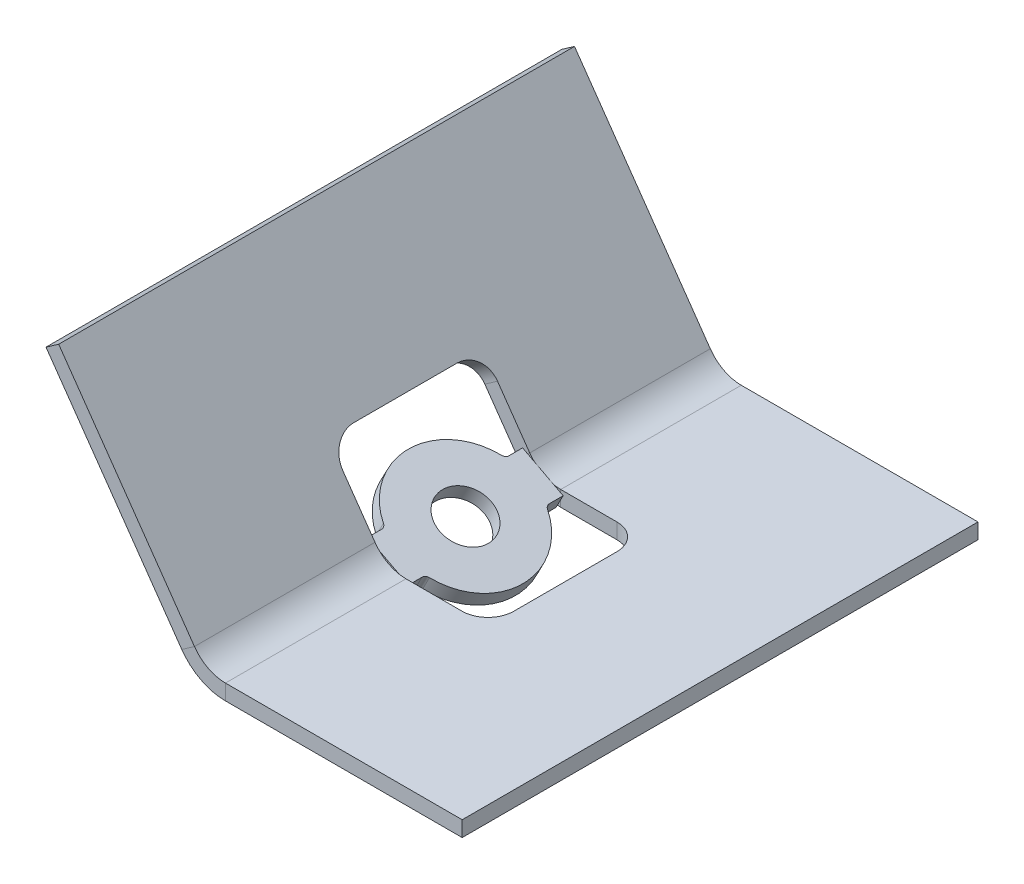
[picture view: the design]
ISO-10303-21;
HEADER;
FILE_DESCRIPTION(('STEP AP214'),'2;1');
FILE_NAME('part.step','',(''),(''),'','','');
FILE_SCHEMA(('AUTOMOTIVE_DESIGN { 1 0 10303 214 1 1 1 1 }'));
ENDSEC;
DATA;
#1=APPLICATION_CONTEXT('core data for automotive mechanical design processes');
#2=APPLICATION_PROTOCOL_DEFINITION('international standard','automotive_design',2000,#1);
#3=PRODUCT_CONTEXT('',#1,'mechanical');
#4=PRODUCT('Part','Part','',(#3));
#5=PRODUCT_RELATED_PRODUCT_CATEGORY('part','',(#4));
#6=PRODUCT_DEFINITION_FORMATION('','',#4);
#7=PRODUCT_DEFINITION_CONTEXT('part definition',#1,'design');
#8=PRODUCT_DEFINITION('design','',#6,#7);
#9=PRODUCT_DEFINITION_SHAPE('','',#8);
#10=(LENGTH_UNIT() NAMED_UNIT(*) SI_UNIT(.MILLI.,.METRE.));
#11=(NAMED_UNIT(*) PLANE_ANGLE_UNIT() SI_UNIT($,.RADIAN.));
#12=(NAMED_UNIT(*) SI_UNIT($,.STERADIAN.) SOLID_ANGLE_UNIT());
#13=UNCERTAINTY_MEASURE_WITH_UNIT(LENGTH_MEASURE(1.E-05),#10,'distance_accuracy_value','');
#14=(GEOMETRIC_REPRESENTATION_CONTEXT(3) GLOBAL_UNCERTAINTY_ASSIGNED_CONTEXT((#13)) GLOBAL_UNIT_ASSIGNED_CONTEXT((#10,
#11,#12)) REPRESENTATION_CONTEXT('',''));
#15=CARTESIAN_POINT('',(0.,0.,0.));
#16=DIRECTION('',(0.,0.,1.));
#17=DIRECTION('',(1.,0.,0.));
#18=AXIS2_PLACEMENT_3D('',#15,#16,#17);
#19=CARTESIAN_POINT('',(-0.740629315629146,-1.42273567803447,0.));
#20=DIRECTION('',(-0.461748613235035,-0.887010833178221,0.));
#21=DIRECTION('',(0.887010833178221,-0.461748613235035,0.));
#22=AXIS2_PLACEMENT_3D('',#19,#20,#21);
#23=PLANE('',#22);
#24=DIRECTION('',(-0.887010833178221,0.461748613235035,0.));
#25=VECTOR('',#24,1.);
#26=CARTESIAN_POINT('',(3.19331177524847,-3.47061578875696,15.));
#27=LINE('',#26,#25);
#28=CARTESIAN_POINT('',(3.19331177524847,-3.47061578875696,15.));
#29=VERTEX_POINT('',#28);
#30=CARTESIAN_POINT('',(-4.67457040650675,0.625144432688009,15.));
#31=VERTEX_POINT('',#30);
#32=EDGE_CURVE('E151',#29,#31,#27,.T.);
#33=ORIENTED_EDGE('',*,*,#32,.T.);
#34=DIRECTION('',(0.,0.,-1.));
#35=VECTOR('',#34,1.);
#36=CARTESIAN_POINT('',(-4.67457040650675,0.625144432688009,15.));
#37=LINE('',#36,#35);
#38=CARTESIAN_POINT('',(-4.67457040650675,0.625144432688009,12.3575962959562));
#39=VERTEX_POINT('',#38);
#40=EDGE_CURVE('E139',#31,#39,#37,.T.);
#41=ORIENTED_EDGE('',*,*,#40,.T.);
#42=CARTESIAN_POINT('',(-5.56158123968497,1.08689304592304,12.3575962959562));
#43=DIRECTION('',(-0.461748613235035,-0.887010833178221,0.));
#44=DIRECTION('',(0.887010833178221,-0.461748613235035,0.));
#45=AXIS2_PLACEMENT_3D('',#42,#43,#44);
#46=CIRCLE('',#45,1.);
#47=CARTESIAN_POINT('',(-5.20447368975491,0.900994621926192,11.442218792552));
#48=VERTEX_POINT('',#47);
#49=EDGE_CURVE('E196',#39,#48,#46,.F.);
#50=ORIENTED_EDGE('',*,*,#49,.T.);
#51=CARTESIAN_POINT('',(-0.740629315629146,-1.42273567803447,0.));
#52=DIRECTION('',(-0.461748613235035,-0.887010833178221,0.));
#53=DIRECTION('',(0.887010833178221,-0.461748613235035,0.));
#54=AXIS2_PLACEMENT_3D('',#51,#52,#53);
#55=CIRCLE('',#54,12.5);
#56=CARTESIAN_POINT('',(-5.20447368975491,0.900994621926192,-11.442218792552));
#57=VERTEX_POINT('',#56);
#58=EDGE_CURVE('E150',#48,#57,#55,.T.);
#59=ORIENTED_EDGE('',*,*,#58,.T.);
#60=CARTESIAN_POINT('',(-5.56158123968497,1.08689304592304,-12.3575962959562));
#61=DIRECTION('',(-0.461748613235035,-0.887010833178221,0.));
#62=DIRECTION('',(0.887010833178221,-0.461748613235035,0.));
#63=AXIS2_PLACEMENT_3D('',#60,#61,#62);
#64=CIRCLE('',#63,1.);
#65=CARTESIAN_POINT('',(-4.67457040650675,0.625144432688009,-12.3575962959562));
#66=VERTEX_POINT('',#65);
#67=EDGE_CURVE('E200',#57,#66,#64,.F.);
#68=ORIENTED_EDGE('',*,*,#67,.T.);
#69=DIRECTION('',(0.,0.,-1.));
#70=VECTOR('',#69,1.);
#71=CARTESIAN_POINT('',(-4.67457040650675,0.625144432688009,-11.6867572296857));
#72=LINE('',#71,#70);
#73=CARTESIAN_POINT('',(-4.67457040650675,0.625144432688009,-15.));
#74=VERTEX_POINT('',#73);
#75=EDGE_CURVE('E204',#66,#74,#72,.T.);
#76=ORIENTED_EDGE('',*,*,#75,.T.);
#77=DIRECTION('',(0.887010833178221,-0.461748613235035,0.));
#78=VECTOR('',#77,1.);
#79=CARTESIAN_POINT('',(-4.67457040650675,0.625144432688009,-15.));
#80=LINE('',#79,#78);
#81=CARTESIAN_POINT('',(3.19331177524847,-3.47061578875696,-15.));
#82=VERTEX_POINT('',#81);
#83=EDGE_CURVE('E214',#74,#82,#80,.T.);
#84=ORIENTED_EDGE('',*,*,#83,.T.);
#85=DIRECTION('',(0.,0.,1.));
#86=VECTOR('',#85,1.);
#87=CARTESIAN_POINT('',(3.19331177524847,-3.47061578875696,-11.6867572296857));
#88=LINE('',#87,#86);
#89=CARTESIAN_POINT('',(3.19331177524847,-3.47061578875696,-12.3575962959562));
#90=VERTEX_POINT('',#89);
#91=EDGE_CURVE('E245',#82,#90,#88,.T.);
#92=ORIENTED_EDGE('',*,*,#91,.T.);
#93=CARTESIAN_POINT('',(4.08032260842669,-3.93236440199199,-12.3575962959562));
#94=DIRECTION('',(-0.461748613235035,-0.887010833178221,0.));
#95=DIRECTION('',(0.887010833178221,-0.461748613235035,0.));
#96=AXIS2_PLACEMENT_3D('',#93,#94,#95);
#97=CIRCLE('',#96,1.);
#98=CARTESIAN_POINT('',(3.72321505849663,-3.74646597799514,-11.442218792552));
#99=VERTEX_POINT('',#98);
#100=EDGE_CURVE('E13',#90,#99,#97,.F.);
#101=ORIENTED_EDGE('',*,*,#100,.T.);
#102=CARTESIAN_POINT('',(-0.740629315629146,-1.42273567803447,0.));
#103=DIRECTION('',(-0.461748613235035,-0.887010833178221,0.));
#104=DIRECTION('',(0.887010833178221,-0.461748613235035,0.));
#105=AXIS2_PLACEMENT_3D('',#102,#103,#104);
#106=CIRCLE('',#105,12.5);
#107=CARTESIAN_POINT('',(3.72321505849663,-3.74646597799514,11.442218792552));
#108=VERTEX_POINT('',#107);
#109=EDGE_CURVE('E249',#99,#108,#106,.T.);
#110=ORIENTED_EDGE('',*,*,#109,.T.);
#111=CARTESIAN_POINT('',(4.08032260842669,-3.93236440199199,12.3575962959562));
#112=DIRECTION('',(-0.461748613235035,-0.887010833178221,0.));
#113=DIRECTION('',(0.887010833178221,-0.461748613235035,0.));
#114=AXIS2_PLACEMENT_3D('',#111,#112,#113);
#115=CIRCLE('',#114,1.);
#116=CARTESIAN_POINT('',(3.19331177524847,-3.47061578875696,12.3575962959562));
#117=VERTEX_POINT('',#116);
#118=EDGE_CURVE('E192',#108,#117,#115,.F.);
#119=ORIENTED_EDGE('',*,*,#118,.T.);
#120=DIRECTION('',(0.,0.,1.));
#121=VECTOR('',#120,1.);
#122=CARTESIAN_POINT('',(3.19331177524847,-3.47061578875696,15.));
#123=LINE('',#122,#121);
#124=EDGE_CURVE('E156',#117,#29,#123,.T.);
#125=ORIENTED_EDGE('',*,*,#124,.T.);
#126=EDGE_LOOP('',(#33,#41,#50,#59,#68,#76,#84,#92,#101,#110,#119,#125));
#127=FACE_BOUND('',#126,.T.);
#128=CARTESIAN_POINT('',(-0.740629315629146,-1.42273567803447,0.));
#129=DIRECTION('',(-0.461748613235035,-0.887010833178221,0.));
#130=DIRECTION('',(0.887010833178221,-0.461748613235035,0.));
#131=AXIS2_PLACEMENT_3D('',#128,#129,#130);
#132=CIRCLE('',#131,5.);
#133=CARTESIAN_POINT('',(3.69442485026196,-3.73147874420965,0.));
#134=VERTEX_POINT('',#133);
#135=EDGE_CURVE('E255',#134,#134,#132,.T.);
#136=ORIENTED_EDGE('',*,*,#135,.F.);
#137=EDGE_LOOP('',(#136));
#138=FACE_BOUND('',#137,.T.);
#139=ADVANCED_FACE('F50',(#127,#138),#23,.T.);
#140=CARTESIAN_POINT('',(0.644616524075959,1.23829682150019,0.));
#141=DIRECTION('',(-0.461748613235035,-0.887010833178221,0.));
#142=DIRECTION('',(0.887010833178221,-0.461748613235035,0.));
#143=AXIS2_PLACEMENT_3D('',#140,#141,#142);
#144=PLANE('',#143);
#145=DIRECTION('',(-0.887010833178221,0.461748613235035,0.));
#146=VECTOR('',#145,1.);
#147=CARTESIAN_POINT('',(4.57855761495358,-0.809583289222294,15.));
#148=LINE('',#147,#146);
#149=CARTESIAN_POINT('',(4.57855761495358,-0.809583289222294,15.));
#150=VERTEX_POINT('',#149);
#151=CARTESIAN_POINT('',(-3.28932456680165,3.28617693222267,15.));
#152=VERTEX_POINT('',#151);
#153=EDGE_CURVE('E164',#150,#152,#148,.T.);
#154=ORIENTED_EDGE('',*,*,#153,.F.);
#155=DIRECTION('',(0.,0.,1.));
#156=VECTOR('',#155,1.);
#157=CARTESIAN_POINT('',(4.57855761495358,-0.809583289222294,15.));
#158=LINE('',#157,#156);
#159=CARTESIAN_POINT('',(4.57855761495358,-0.809583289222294,12.3575962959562));
#160=VERTEX_POINT('',#159);
#161=EDGE_CURVE('E160',#160,#150,#158,.T.);
#162=ORIENTED_EDGE('',*,*,#161,.F.);
#163=CARTESIAN_POINT('',(5.4655684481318,-1.27133190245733,12.3575962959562));
#164=DIRECTION('',(-0.461748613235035,-0.887010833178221,0.));
#165=DIRECTION('',(0.887010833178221,-0.461748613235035,0.));
#166=AXIS2_PLACEMENT_3D('',#163,#164,#165);
#167=CIRCLE('',#166,1.);
#168=CARTESIAN_POINT('',(5.10846089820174,-1.08543347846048,11.442218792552));
#169=VERTEX_POINT('',#168);
#170=EDGE_CURVE('E190',#160,#169,#167,.T.);
#171=ORIENTED_EDGE('',*,*,#170,.T.);
#172=CARTESIAN_POINT('',(0.644616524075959,1.23829682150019,0.));
#173=DIRECTION('',(-0.461748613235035,-0.887010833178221,0.));
#174=DIRECTION('',(0.887010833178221,-0.461748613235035,0.));
#175=AXIS2_PLACEMENT_3D('',#172,#173,#174);
#176=CIRCLE('',#175,12.5);
#177=CARTESIAN_POINT('',(5.10846089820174,-1.08543347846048,-11.442218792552));
#178=VERTEX_POINT('',#177);
#179=EDGE_CURVE('E237',#178,#169,#176,.T.);
#180=ORIENTED_EDGE('',*,*,#179,.F.);
#181=CARTESIAN_POINT('',(5.4655684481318,-1.27133190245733,-12.3575962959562));
#182=DIRECTION('',(-0.461748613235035,-0.887010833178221,0.));
#183=DIRECTION('',(0.887010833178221,-0.461748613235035,0.));
#184=AXIS2_PLACEMENT_3D('',#181,#182,#183);
#185=CIRCLE('',#184,1.);
#186=CARTESIAN_POINT('',(4.57855761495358,-0.809583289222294,-12.3575962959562));
#187=VERTEX_POINT('',#186);
#188=EDGE_CURVE('E58',#178,#187,#185,.T.);
#189=ORIENTED_EDGE('',*,*,#188,.T.);
#190=DIRECTION('',(0.,0.,1.));
#191=VECTOR('',#190,1.);
#192=CARTESIAN_POINT('',(4.57855761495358,-0.809583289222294,-11.6867572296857));
#193=LINE('',#192,#191);
#194=CARTESIAN_POINT('',(4.57855761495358,-0.809583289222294,-15.));
#195=VERTEX_POINT('',#194);
#196=EDGE_CURVE('E235',#195,#187,#193,.T.);
#197=ORIENTED_EDGE('',*,*,#196,.F.);
#198=DIRECTION('',(0.887010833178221,-0.461748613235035,0.));
#199=VECTOR('',#198,1.);
#200=CARTESIAN_POINT('',(-3.28932456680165,3.28617693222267,-15.));
#201=LINE('',#200,#199);
#202=CARTESIAN_POINT('',(-3.28932456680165,3.28617693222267,-15.));
#203=VERTEX_POINT('',#202);
#204=EDGE_CURVE('E229',#203,#195,#201,.T.);
#205=ORIENTED_EDGE('',*,*,#204,.F.);
#206=DIRECTION('',(0.,0.,-1.));
#207=VECTOR('',#206,1.);
#208=CARTESIAN_POINT('',(-3.28932456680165,3.28617693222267,-11.6867572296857));
#209=LINE('',#208,#207);
#210=CARTESIAN_POINT('',(-3.28932456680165,3.28617693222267,-12.3575962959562));
#211=VERTEX_POINT('',#210);
#212=EDGE_CURVE('E223',#211,#203,#209,.T.);
#213=ORIENTED_EDGE('',*,*,#212,.F.);
#214=CARTESIAN_POINT('',(-4.17633539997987,3.74792554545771,-12.3575962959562));
#215=DIRECTION('',(-0.461748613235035,-0.887010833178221,0.));
#216=DIRECTION('',(0.887010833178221,-0.461748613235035,0.));
#217=AXIS2_PLACEMENT_3D('',#214,#215,#216);
#218=CIRCLE('',#217,1.);
#219=CARTESIAN_POINT('',(-3.81922785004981,3.56202712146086,-11.442218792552));
#220=VERTEX_POINT('',#219);
#221=EDGE_CURVE('E198',#211,#220,#218,.T.);
#222=ORIENTED_EDGE('',*,*,#221,.T.);
#223=CARTESIAN_POINT('',(0.644616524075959,1.23829682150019,0.));
#224=DIRECTION('',(-0.461748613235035,-0.887010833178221,0.));
#225=DIRECTION('',(0.887010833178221,-0.461748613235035,0.));
#226=AXIS2_PLACEMENT_3D('',#223,#224,#225);
#227=CIRCLE('',#226,12.5);
#228=CARTESIAN_POINT('',(-3.81922785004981,3.56202712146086,11.442218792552));
#229=VERTEX_POINT('',#228);
#230=EDGE_CURVE('E221',#229,#220,#227,.T.);
#231=ORIENTED_EDGE('',*,*,#230,.F.);
#232=CARTESIAN_POINT('',(-4.17633539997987,3.74792554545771,12.3575962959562));
#233=DIRECTION('',(-0.461748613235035,-0.887010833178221,0.));
#234=DIRECTION('',(0.887010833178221,-0.461748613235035,0.));
#235=AXIS2_PLACEMENT_3D('',#232,#233,#234);
#236=CIRCLE('',#235,1.);
#237=CARTESIAN_POINT('',(-3.28932456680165,3.28617693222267,12.3575962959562));
#238=VERTEX_POINT('',#237);
#239=EDGE_CURVE('E194',#229,#238,#236,.T.);
#240=ORIENTED_EDGE('',*,*,#239,.T.);
#241=DIRECTION('',(0.,0.,-1.));
#242=VECTOR('',#241,1.);
#243=CARTESIAN_POINT('',(-3.28932456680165,3.28617693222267,15.));
#244=LINE('',#243,#242);
#245=EDGE_CURVE('E227',#152,#238,#244,.T.);
#246=ORIENTED_EDGE('',*,*,#245,.F.);
#247=EDGE_LOOP('',(#154,#162,#171,#180,#189,#197,#205,#213,#222,#231,#240,#246));
#248=FACE_BOUND('',#247,.T.);
#249=CARTESIAN_POINT('',(0.644616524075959,1.23829682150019,0.));
#250=DIRECTION('',(-0.461748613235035,-0.887010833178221,0.));
#251=DIRECTION('',(0.887010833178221,-0.461748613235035,0.));
#252=AXIS2_PLACEMENT_3D('',#249,#250,#251);
#253=CIRCLE('',#252,5.);
#254=CARTESIAN_POINT('',(5.07967068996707,-1.07044624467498,0.));
#255=VERTEX_POINT('',#254);
#256=EDGE_CURVE('E257',#255,#255,#253,.T.);
#257=ORIENTED_EDGE('',*,*,#256,.T.);
#258=EDGE_LOOP('',(#257));
#259=FACE_BOUND('',#258,.T.);
#260=ADVANCED_FACE('F219',(#248,#259),#144,.F.);
#261=CARTESIAN_POINT('',(3.19331177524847,-3.47061578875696,15.));
#262=DIRECTION('',(0.,0.,-1.));
#263=DIRECTION('',(-1.,0.,0.));
#264=AXIS2_PLACEMENT_3D('',#261,#262,#263);
#265=PLANE('',#264);
#266=ORIENTED_EDGE('',*,*,#153,.T.);
#267=DIRECTION('',(0.461748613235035,0.887010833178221,0.));
#268=VECTOR('',#267,1.);
#269=CARTESIAN_POINT('',(-4.67457040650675,0.625144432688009,15.));
#270=LINE('',#269,#268);
#271=EDGE_CURVE('E144',#31,#152,#270,.T.);
#272=ORIENTED_EDGE('',*,*,#271,.F.);
#273=ORIENTED_EDGE('',*,*,#32,.F.);
#274=DIRECTION('',(0.461748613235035,0.887010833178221,0.));
#275=VECTOR('',#274,1.);
#276=CARTESIAN_POINT('',(3.19331177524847,-3.47061578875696,15.));
#277=LINE('',#276,#275);
#278=EDGE_CURVE('E241',#29,#150,#277,.T.);
#279=ORIENTED_EDGE('',*,*,#278,.T.);
#280=EDGE_LOOP('',(#266,#272,#273,#279));
#281=FACE_BOUND('',#280,.T.);
#282=ADVANCED_FACE('F162',(#281),#265,.F.);
#283=CARTESIAN_POINT('',(-4.67457040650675,0.625144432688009,15.));
#284=DIRECTION('',(0.887010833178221,-0.461748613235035,0.));
#285=DIRECTION('',(0.461748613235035,0.887010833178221,0.));
#286=AXIS2_PLACEMENT_3D('',#283,#284,#285);
#287=PLANE('',#286);
#288=ORIENTED_EDGE('',*,*,#245,.T.);
#289=DIRECTION('',(-0.461748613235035,-0.887010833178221,0.));
#290=VECTOR('',#289,1.);
#291=CARTESIAN_POINT('',(-4.67457040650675,0.625144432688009,12.3575962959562));
#292=LINE('',#291,#290);
#293=EDGE_CURVE('E147',#238,#39,#292,.T.);
#294=ORIENTED_EDGE('',*,*,#293,.T.);
#295=ORIENTED_EDGE('',*,*,#40,.F.);
#296=ORIENTED_EDGE('',*,*,#271,.T.);
#297=EDGE_LOOP('',(#288,#294,#295,#296));
#298=FACE_BOUND('',#297,.T.);
#299=ADVANCED_FACE('F142',(#298),#287,.F.);
#300=CARTESIAN_POINT('',(-0.740629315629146,-1.42273567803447,0.));
#301=DIRECTION('',(0.461748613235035,0.887010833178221,0.));
#302=DIRECTION('',(-0.887010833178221,0.461748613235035,0.));
#303=AXIS2_PLACEMENT_3D('',#300,#301,#302);
#304=CYLINDRICAL_SURFACE('',#303,12.5);
#305=ORIENTED_EDGE('',*,*,#58,.F.);
#306=DIRECTION('',(0.461748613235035,0.887010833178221,0.));
#307=VECTOR('',#306,1.);
#308=CARTESIAN_POINT('',(-5.20447368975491,0.900994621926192,11.442218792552));
#309=LINE('',#308,#307);
#310=EDGE_CURVE('E182',#48,#229,#309,.T.);
#311=ORIENTED_EDGE('',*,*,#310,.T.);
#312=ORIENTED_EDGE('',*,*,#230,.T.);
#313=DIRECTION('',(0.461748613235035,0.887010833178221,0.));
#314=VECTOR('',#313,1.);
#315=CARTESIAN_POINT('',(-5.20447368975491,0.900994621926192,-11.442218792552));
#316=LINE('',#315,#314);
#317=EDGE_CURVE('E180',#220,#57,#316,.F.);
#318=ORIENTED_EDGE('',*,*,#317,.T.);
#319=EDGE_LOOP('',(#305,#311,#312,#318));
#320=FACE_BOUND('',#319,.T.);
#321=ADVANCED_FACE('F225',(#320),#304,.T.);
#322=CARTESIAN_POINT('',(-4.67457040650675,0.625144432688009,-11.6867572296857));
#323=DIRECTION('',(0.887010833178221,-0.461748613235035,0.));
#324=DIRECTION('',(0.461748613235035,0.887010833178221,0.));
#325=AXIS2_PLACEMENT_3D('',#322,#323,#324);
#326=PLANE('',#325);
#327=ORIENTED_EDGE('',*,*,#75,.F.);
#328=DIRECTION('',(-0.461748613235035,-0.887010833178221,0.));
#329=VECTOR('',#328,1.);
#330=CARTESIAN_POINT('',(-3.28932456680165,3.28617693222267,-12.3575962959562));
#331=LINE('',#330,#329);
#332=EDGE_CURVE('E186',#66,#211,#331,.F.);
#333=ORIENTED_EDGE('',*,*,#332,.T.);
#334=ORIENTED_EDGE('',*,*,#212,.T.);
#335=DIRECTION('',(0.461748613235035,0.887010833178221,0.));
#336=VECTOR('',#335,1.);
#337=CARTESIAN_POINT('',(-4.67457040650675,0.625144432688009,-15.));
#338=LINE('',#337,#336);
#339=EDGE_CURVE('E166',#74,#203,#338,.T.);
#340=ORIENTED_EDGE('',*,*,#339,.F.);
#341=EDGE_LOOP('',(#327,#333,#334,#340));
#342=FACE_BOUND('',#341,.T.);
#343=ADVANCED_FACE('F211',(#342),#326,.F.);
#344=CARTESIAN_POINT('',(-4.67457040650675,0.625144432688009,-15.));
#345=DIRECTION('',(0.,0.,1.));
#346=DIRECTION('',(1.,0.,0.));
#347=AXIS2_PLACEMENT_3D('',#344,#345,#346);
#348=PLANE('',#347);
#349=ORIENTED_EDGE('',*,*,#204,.T.);
#350=DIRECTION('',(0.461748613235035,0.887010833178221,0.));
#351=VECTOR('',#350,1.);
#352=CARTESIAN_POINT('',(3.19331177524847,-3.47061578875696,-15.));
#353=LINE('',#352,#351);
#354=EDGE_CURVE('E172',#82,#195,#353,.T.);
#355=ORIENTED_EDGE('',*,*,#354,.F.);
#356=ORIENTED_EDGE('',*,*,#83,.F.);
#357=ORIENTED_EDGE('',*,*,#339,.T.);
#358=EDGE_LOOP('',(#349,#355,#356,#357));
#359=FACE_BOUND('',#358,.T.);
#360=ADVANCED_FACE('F247',(#359),#348,.F.);
#361=CARTESIAN_POINT('',(3.19331177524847,-3.47061578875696,-11.6867572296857));
#362=DIRECTION('',(-0.887010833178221,0.461748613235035,0.));
#363=DIRECTION('',(-0.461748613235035,-0.887010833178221,0.));
#364=AXIS2_PLACEMENT_3D('',#361,#362,#363);
#365=PLANE('',#364);
#366=ORIENTED_EDGE('',*,*,#196,.T.);
#367=DIRECTION('',(-0.461748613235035,-0.887010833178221,0.));
#368=VECTOR('',#367,1.);
#369=CARTESIAN_POINT('',(3.19331177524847,-3.47061578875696,-12.3575962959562));
#370=LINE('',#369,#368);
#371=EDGE_CURVE('E65',#187,#90,#370,.T.);
#372=ORIENTED_EDGE('',*,*,#371,.T.);
#373=ORIENTED_EDGE('',*,*,#91,.F.);
#374=ORIENTED_EDGE('',*,*,#354,.T.);
#375=EDGE_LOOP('',(#366,#372,#373,#374));
#376=FACE_BOUND('',#375,.T.);
#377=ADVANCED_FACE('F244',(#376),#365,.F.);
#378=CARTESIAN_POINT('',(-0.740629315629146,-1.42273567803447,0.));
#379=DIRECTION('',(0.461748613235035,0.887010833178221,0.));
#380=DIRECTION('',(-0.887010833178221,0.461748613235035,0.));
#381=AXIS2_PLACEMENT_3D('',#378,#379,#380);
#382=CYLINDRICAL_SURFACE('',#381,12.5);
#383=ORIENTED_EDGE('',*,*,#179,.T.);
#384=DIRECTION('',(0.461748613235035,0.887010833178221,0.));
#385=VECTOR('',#384,1.);
#386=CARTESIAN_POINT('',(3.72321505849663,-3.74646597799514,11.442218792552));
#387=LINE('',#386,#385);
#388=EDGE_CURVE('E178',#169,#108,#387,.F.);
#389=ORIENTED_EDGE('',*,*,#388,.T.);
#390=ORIENTED_EDGE('',*,*,#109,.F.);
#391=DIRECTION('',(0.461748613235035,0.887010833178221,0.));
#392=VECTOR('',#391,1.);
#393=CARTESIAN_POINT('',(3.72321505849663,-3.74646597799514,-11.442218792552));
#394=LINE('',#393,#392);
#395=EDGE_CURVE('E169',#99,#178,#394,.T.);
#396=ORIENTED_EDGE('',*,*,#395,.T.);
#397=EDGE_LOOP('',(#383,#389,#390,#396));
#398=FACE_BOUND('',#397,.T.);
#399=ADVANCED_FACE('F277',(#398),#382,.T.);
#400=CARTESIAN_POINT('',(3.19331177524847,-3.47061578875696,15.));
#401=DIRECTION('',(-0.887010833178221,0.461748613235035,0.));
#402=DIRECTION('',(-0.461748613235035,-0.887010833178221,0.));
#403=AXIS2_PLACEMENT_3D('',#400,#401,#402);
#404=PLANE('',#403);
#405=ORIENTED_EDGE('',*,*,#124,.F.);
#406=DIRECTION('',(-0.461748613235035,-0.887010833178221,0.));
#407=VECTOR('',#406,1.);
#408=CARTESIAN_POINT('',(4.57855761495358,-0.809583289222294,12.3575962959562));
#409=LINE('',#408,#407);
#410=EDGE_CURVE('E165',#117,#160,#409,.F.);
#411=ORIENTED_EDGE('',*,*,#410,.T.);
#412=ORIENTED_EDGE('',*,*,#161,.T.);
#413=ORIENTED_EDGE('',*,*,#278,.F.);
#414=EDGE_LOOP('',(#405,#411,#412,#413));
#415=FACE_BOUND('',#414,.T.);
#416=ADVANCED_FACE('F268',(#415),#404,.F.);
#417=CARTESIAN_POINT('',(-0.740629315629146,-1.42273567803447,0.));
#418=DIRECTION('',(0.461748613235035,0.887010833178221,0.));
#419=DIRECTION('',(-0.887010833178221,0.461748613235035,0.));
#420=AXIS2_PLACEMENT_3D('',#417,#418,#419);
#421=CYLINDRICAL_SURFACE('',#420,5.);
#422=ORIENTED_EDGE('',*,*,#135,.T.);
#423=EDGE_LOOP('',(#422));
#424=FACE_BOUND('',#423,.T.);
#425=ORIENTED_EDGE('',*,*,#256,.F.);
#426=EDGE_LOOP('',(#425));
#427=FACE_BOUND('',#426,.T.);
#428=ADVANCED_FACE('F265',(#424,#427),#421,.F.);
#429=CARTESIAN_POINT('',(4.08032260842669,-3.93236440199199,12.3575962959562));
#430=DIRECTION('',(0.461748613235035,0.887010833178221,0.));
#431=DIRECTION('',(-0.887010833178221,0.461748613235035,0.));
#432=AXIS2_PLACEMENT_3D('',#429,#430,#431);
#433=CYLINDRICAL_SURFACE('',#432,1.);
#434=ORIENTED_EDGE('',*,*,#118,.F.);
#435=ORIENTED_EDGE('',*,*,#388,.F.);
#436=ORIENTED_EDGE('',*,*,#170,.F.);
#437=ORIENTED_EDGE('',*,*,#410,.F.);
#438=EDGE_LOOP('',(#434,#435,#436,#437));
#439=FACE_BOUND('',#438,.T.);
#440=ADVANCED_FACE('F267',(#439),#433,.F.);
#441=CARTESIAN_POINT('',(-5.56158123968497,1.08689304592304,12.3575962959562));
#442=DIRECTION('',(0.461748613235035,0.887010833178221,0.));
#443=DIRECTION('',(-0.887010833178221,0.461748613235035,0.));
#444=AXIS2_PLACEMENT_3D('',#441,#442,#443);
#445=CYLINDRICAL_SURFACE('',#444,1.);
#446=ORIENTED_EDGE('',*,*,#49,.F.);
#447=ORIENTED_EDGE('',*,*,#293,.F.);
#448=ORIENTED_EDGE('',*,*,#239,.F.);
#449=ORIENTED_EDGE('',*,*,#310,.F.);
#450=EDGE_LOOP('',(#446,#447,#448,#449));
#451=FACE_BOUND('',#450,.T.);
#452=ADVANCED_FACE('F274',(#451),#445,.F.);
#453=CARTESIAN_POINT('',(-5.56158123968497,1.08689304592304,-12.3575962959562));
#454=DIRECTION('',(0.461748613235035,0.887010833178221,0.));
#455=DIRECTION('',(-0.887010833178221,0.461748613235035,0.));
#456=AXIS2_PLACEMENT_3D('',#453,#454,#455);
#457=CYLINDRICAL_SURFACE('',#456,1.);
#458=ORIENTED_EDGE('',*,*,#67,.F.);
#459=ORIENTED_EDGE('',*,*,#317,.F.);
#460=ORIENTED_EDGE('',*,*,#221,.F.);
#461=ORIENTED_EDGE('',*,*,#332,.F.);
#462=EDGE_LOOP('',(#458,#459,#460,#461));
#463=FACE_BOUND('',#462,.T.);
#464=ADVANCED_FACE('F216',(#463),#457,.F.);
#465=CARTESIAN_POINT('',(4.08032260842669,-3.93236440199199,-12.3575962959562));
#466=DIRECTION('',(0.461748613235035,0.887010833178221,0.));
#467=DIRECTION('',(-0.887010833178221,0.461748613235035,0.));
#468=AXIS2_PLACEMENT_3D('',#465,#466,#467);
#469=CYLINDRICAL_SURFACE('',#468,1.);
#470=ORIENTED_EDGE('',*,*,#100,.F.);
#471=ORIENTED_EDGE('',*,*,#371,.F.);
#472=ORIENTED_EDGE('',*,*,#188,.F.);
#473=ORIENTED_EDGE('',*,*,#395,.F.);
#474=EDGE_LOOP('',(#470,#471,#472,#473));
#475=FACE_BOUND('',#474,.T.);
#476=ADVANCED_FACE('F52',(#475),#469,.F.);
#477=CLOSED_SHELL('',(#139,#260,#282,#299,#321,#343,#360,#377,#399,#416,#428,#440,#452,#464,#476));
#478=MANIFOLD_SOLID_BREP('B2',#477);
#479=CARTESIAN_POINT('',(-30.6837652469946,39.0013097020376,50.));
#480=DIRECTION('',(0.,0.,1.));
#481=DIRECTION('',(0.573576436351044,-0.819152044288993,0.));
#482=AXIS2_PLACEMENT_3D('',#479,#480,#481);
#483=PLANE('',#482);
#484=DIRECTION('',(0.573576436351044,-0.819152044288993,0.));
#485=VECTOR('',#484,1.);
#486=CARTESIAN_POINT('',(-30.6837652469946,39.0013097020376,50.));
#487=LINE('',#486,#485);
#488=CARTESIAN_POINT('',(-30.6837652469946,39.0013097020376,50.));
#489=VERTEX_POINT('',#488);
#490=CARTESIAN_POINT('',(-4.36016463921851,1.40731196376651,50.));
#491=VERTEX_POINT('',#490);
#492=EDGE_CURVE('E589',#489,#491,#487,.T.);
#493=ORIENTED_EDGE('',*,*,#492,.T.);
#494=DIRECTION('',(0.819152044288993,0.573576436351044,0.));
#495=VECTOR('',#494,1.);
#496=CARTESIAN_POINT('',(-4.36016463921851,1.40731196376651,50.));
#497=LINE('',#496,#495);
#498=CARTESIAN_POINT('',(-1.90270850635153,3.12804127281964,50.));
#499=VERTEX_POINT('',#498);
#500=EDGE_CURVE('E48',#491,#499,#497,.T.);
#501=ORIENTED_EDGE('',*,*,#500,.T.);
#502=DIRECTION('',(0.573576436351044,-0.819152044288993,0.));
#503=VECTOR('',#502,1.);
#504=CARTESIAN_POINT('',(-28.2263091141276,40.7220390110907,50.));
#505=LINE('',#504,#503);
#506=CARTESIAN_POINT('',(-28.2263091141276,40.7220390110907,50.));
#507=VERTEX_POINT('',#506);
#508=EDGE_CURVE('E584',#507,#499,#505,.T.);
#509=ORIENTED_EDGE('',*,*,#508,.F.);
#510=DIRECTION('',(0.819152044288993,0.573576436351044,0.));
#511=VECTOR('',#510,1.);
#512=CARTESIAN_POINT('',(-30.6837652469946,39.0013097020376,50.));
#513=LINE('',#512,#511);
#514=EDGE_CURVE('E609',#489,#507,#513,.T.);
#515=ORIENTED_EDGE('',*,*,#514,.F.);
#516=EDGE_LOOP('',(#493,#501,#509,#515));
#517=FACE_BOUND('',#516,.T.);
#518=ADVANCED_FACE('F402',(#517),#483,.T.);
#519=CARTESIAN_POINT('',(-30.6837652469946,39.0013097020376,-50.));
#520=DIRECTION('',(0.,0.,-1.));
#521=DIRECTION('',(-0.573576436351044,0.819152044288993,0.));
#522=AXIS2_PLACEMENT_3D('',#519,#520,#521);
#523=PLANE('',#522);
#524=DIRECTION('',(-0.573576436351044,0.819152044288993,0.));
#525=VECTOR('',#524,1.);
#526=CARTESIAN_POINT('',(-28.2263091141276,40.7220390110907,-50.));
#527=LINE('',#526,#525);
#528=CARTESIAN_POINT('',(-1.90270850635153,3.12804127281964,-50.));
#529=VERTEX_POINT('',#528);
#530=CARTESIAN_POINT('',(-28.2263091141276,40.7220390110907,-50.));
#531=VERTEX_POINT('',#530);
#532=EDGE_CURVE('E594',#529,#531,#527,.T.);
#533=ORIENTED_EDGE('',*,*,#532,.F.);
#534=DIRECTION('',(-0.819152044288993,-0.573576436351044,0.));
#535=VECTOR('',#534,1.);
#536=CARTESIAN_POINT('',(-4.36016463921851,1.40731196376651,-50.));
#537=LINE('',#536,#535);
#538=CARTESIAN_POINT('',(-4.36016463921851,1.40731196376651,-50.));
#539=VERTEX_POINT('',#538);
#540=EDGE_CURVE('E615',#529,#539,#537,.T.);
#541=ORIENTED_EDGE('',*,*,#540,.T.);
#542=DIRECTION('',(-0.573576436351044,0.819152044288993,0.));
#543=VECTOR('',#542,1.);
#544=CARTESIAN_POINT('',(-30.6837652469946,39.0013097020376,-50.));
#545=LINE('',#544,#543);
#546=CARTESIAN_POINT('',(-30.6837652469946,39.0013097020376,-50.));
#547=VERTEX_POINT('',#546);
#548=EDGE_CURVE('E587',#539,#547,#545,.T.);
#549=ORIENTED_EDGE('',*,*,#548,.T.);
#550=DIRECTION('',(0.819152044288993,0.573576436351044,0.));
#551=VECTOR('',#550,1.);
#552=CARTESIAN_POINT('',(-30.6837652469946,39.0013097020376,-50.));
#553=LINE('',#552,#551);
#554=EDGE_CURVE('E590',#547,#531,#553,.T.);
#555=ORIENTED_EDGE('',*,*,#554,.T.);
#556=EDGE_LOOP('',(#533,#541,#549,#555));
#557=FACE_BOUND('',#556,.T.);
#558=ADVANCED_FACE('F814',(#557),#523,.T.);
#559=CARTESIAN_POINT('',(26.6738783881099,-42.9138947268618,-50.));
#560=DIRECTION('',(-0.819152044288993,-0.573576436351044,0.));
#561=DIRECTION('',(0.,0.,-1.));
#562=AXIS2_PLACEMENT_3D('',#559,#560,#561);
#563=PLANE('',#562);
#564=ORIENTED_EDGE('',*,*,#548,.F.);
#565=DIRECTION('',(0.,0.,1.));
#566=VECTOR('',#565,1.);
#567=CARTESIAN_POINT('',(-4.36016463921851,1.40731196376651,-50.));
#568=LINE('',#567,#566);
#569=CARTESIAN_POINT('',(-4.36016463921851,1.40731196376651,-15.));
#570=VERTEX_POINT('',#569);
#571=EDGE_CURVE('E611',#539,#570,#568,.T.);
#572=ORIENTED_EDGE('',*,*,#571,.T.);
#573=DIRECTION('',(-0.573576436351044,0.819152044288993,0.));
#574=VECTOR('',#573,1.);
#575=CARTESIAN_POINT('',(-4.87282561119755,2.13946770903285,-15.));
#576=LINE('',#575,#574);
#577=CARTESIAN_POINT('',(-10.608589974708,10.3309881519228,-15.));
#578=VERTEX_POINT('',#577);
#579=EDGE_CURVE('E406',#570,#578,#576,.T.);
#580=ORIENTED_EDGE('',*,*,#579,.T.);
#581=CARTESIAN_POINT('',(-10.608589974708,10.3309881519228,-10.));
#582=DIRECTION('',(0.819152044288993,0.573576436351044,0.));
#583=DIRECTION('',(0.,0.,1.));
#584=AXIS2_PLACEMENT_3D('',#581,#582,#583);
#585=CIRCLE('',#584,5.);
#586=CARTESIAN_POINT('',(-13.4764721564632,14.4267483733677,-10.));
#587=VERTEX_POINT('',#586);
#588=EDGE_CURVE('E634',#578,#587,#585,.T.);
#589=ORIENTED_EDGE('',*,*,#588,.T.);
#590=DIRECTION('',(0.,0.,1.));
#591=VECTOR('',#590,1.);
#592=CARTESIAN_POINT('',(-13.4764721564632,14.4267483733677,-10.));
#593=LINE('',#592,#591);
#594=CARTESIAN_POINT('',(-13.4764721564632,14.4267483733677,10.));
#595=VERTEX_POINT('',#594);
#596=EDGE_CURVE('E635',#587,#595,#593,.T.);
#597=ORIENTED_EDGE('',*,*,#596,.T.);
#598=CARTESIAN_POINT('',(-10.608589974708,10.3309881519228,10.));
#599=DIRECTION('',(0.819152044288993,0.573576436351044,0.));
#600=DIRECTION('',(0.,0.,1.));
#601=AXIS2_PLACEMENT_3D('',#598,#599,#600);
#602=CIRCLE('',#601,5.);
#603=CARTESIAN_POINT('',(-10.608589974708,10.3309881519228,15.));
#604=VERTEX_POINT('',#603);
#605=EDGE_CURVE('E568',#595,#604,#602,.T.);
#606=ORIENTED_EDGE('',*,*,#605,.T.);
#607=DIRECTION('',(0.573576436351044,-0.819152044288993,0.));
#608=VECTOR('',#607,1.);
#609=CARTESIAN_POINT('',(-10.608589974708,10.3309881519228,15.));
#610=LINE('',#609,#608);
#611=CARTESIAN_POINT('',(-4.36016463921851,1.40731196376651,15.));
#612=VERTEX_POINT('',#611);
#613=EDGE_CURVE('E563',#604,#612,#610,.T.);
#614=ORIENTED_EDGE('',*,*,#613,.T.);
#615=DIRECTION('',(0.,0.,1.));
#616=VECTOR('',#615,1.);
#617=CARTESIAN_POINT('',(-4.36016463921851,1.40731196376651,-50.));
#618=LINE('',#617,#616);
#619=EDGE_CURVE('E541',#612,#491,#618,.T.);
#620=ORIENTED_EDGE('',*,*,#619,.T.);
#621=ORIENTED_EDGE('',*,*,#492,.F.);
#622=DIRECTION('',(0.,0.,1.));
#623=VECTOR('',#622,1.);
#624=CARTESIAN_POINT('',(-30.6837652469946,39.0013097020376,50.));
#625=LINE('',#624,#623);
#626=EDGE_CURVE('E591',#547,#489,#625,.T.);
#627=ORIENTED_EDGE('',*,*,#626,.F.);
#628=EDGE_LOOP('',(#564,#572,#580,#589,#597,#606,#614,#620,#621,#627));
#629=FACE_BOUND('',#628,.T.);
#630=ADVANCED_FACE('F565',(#629),#563,.T.);
#631=CARTESIAN_POINT('',(-30.6837652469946,39.0013097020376,50.));
#632=DIRECTION('',(-0.573576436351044,0.819152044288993,0.));
#633=DIRECTION('',(0.,0.,1.));
#634=AXIS2_PLACEMENT_3D('',#631,#632,#633);
#635=PLANE('',#634);
#636=DIRECTION('',(0.,0.,1.));
#637=VECTOR('',#636,1.);
#638=CARTESIAN_POINT('',(-28.2263091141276,40.7220390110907,50.));
#639=LINE('',#638,#637);
#640=EDGE_CURVE('E588',#531,#507,#639,.T.);
#641=ORIENTED_EDGE('',*,*,#640,.F.);
#642=ORIENTED_EDGE('',*,*,#554,.F.);
#643=ORIENTED_EDGE('',*,*,#626,.T.);
#644=ORIENTED_EDGE('',*,*,#514,.T.);
#645=EDGE_LOOP('',(#641,#642,#643,#644));
#646=FACE_BOUND('',#645,.T.);
#647=ADVANCED_FACE('F823',(#646),#635,.T.);
#648=CARTESIAN_POINT('',(29.1313345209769,-41.1931654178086,-50.));
#649=DIRECTION('',(-0.819152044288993,-0.573576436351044,0.));
#650=DIRECTION('',(0.,0.,-1.));
#651=AXIS2_PLACEMENT_3D('',#648,#649,#650);
#652=PLANE('',#651);
#653=DIRECTION('',(0.,0.,1.));
#654=VECTOR('',#653,1.);
#655=CARTESIAN_POINT('',(-1.90270850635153,3.12804127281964,-50.));
#656=LINE('',#655,#654);
#657=CARTESIAN_POINT('',(-1.90270850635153,3.12804127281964,-15.));
#658=VERTEX_POINT('',#657);
#659=EDGE_CURVE('E617',#529,#658,#656,.T.);
#660=ORIENTED_EDGE('',*,*,#659,.F.);
#661=ORIENTED_EDGE('',*,*,#532,.T.);
#662=ORIENTED_EDGE('',*,*,#640,.T.);
#663=ORIENTED_EDGE('',*,*,#508,.T.);
#664=DIRECTION('',(0.,0.,1.));
#665=VECTOR('',#664,1.);
#666=CARTESIAN_POINT('',(-1.90270850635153,3.12804127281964,-50.));
#667=LINE('',#666,#665);
#668=CARTESIAN_POINT('',(-1.90270850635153,3.12804127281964,15.));
#669=VERTEX_POINT('',#668);
#670=EDGE_CURVE('E411',#669,#499,#667,.T.);
#671=ORIENTED_EDGE('',*,*,#670,.F.);
#672=DIRECTION('',(0.573576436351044,-0.819152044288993,0.));
#673=VECTOR('',#672,1.);
#674=CARTESIAN_POINT('',(9.05615924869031,-12.5228438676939,15.));
#675=LINE('',#674,#673);
#676=CARTESIAN_POINT('',(-8.15113384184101,12.0517174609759,15.));
#677=VERTEX_POINT('',#676);
#678=EDGE_CURVE('E575',#677,#669,#675,.T.);
#679=ORIENTED_EDGE('',*,*,#678,.F.);
#680=CARTESIAN_POINT('',(-8.15113384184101,12.0517174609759,10.));
#681=DIRECTION('',(0.819152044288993,0.573576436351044,0.));
#682=DIRECTION('',(0.,0.,1.));
#683=AXIS2_PLACEMENT_3D('',#680,#681,#682);
#684=CIRCLE('',#683,5.);
#685=CARTESIAN_POINT('',(-11.0190160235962,16.1474776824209,10.));
#686=VERTEX_POINT('',#685);
#687=EDGE_CURVE('E583',#686,#677,#684,.T.);
#688=ORIENTED_EDGE('',*,*,#687,.F.);
#689=DIRECTION('',(0.,0.,1.));
#690=VECTOR('',#689,1.);
#691=CARTESIAN_POINT('',(-11.0190160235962,16.1474776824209,-10.));
#692=LINE('',#691,#690);
#693=CARTESIAN_POINT('',(-11.0190160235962,16.1474776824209,-10.));
#694=VERTEX_POINT('',#693);
#695=EDGE_CURVE('E646',#694,#686,#692,.T.);
#696=ORIENTED_EDGE('',*,*,#695,.F.);
#697=CARTESIAN_POINT('',(-8.15113384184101,12.0517174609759,-10.));
#698=DIRECTION('',(0.819152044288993,0.573576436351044,0.));
#699=DIRECTION('',(0.,0.,1.));
#700=AXIS2_PLACEMENT_3D('',#697,#698,#699);
#701=CIRCLE('',#700,5.);
#702=CARTESIAN_POINT('',(-8.15113384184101,12.0517174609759,-15.));
#703=VERTEX_POINT('',#702);
#704=EDGE_CURVE('E643',#703,#694,#701,.T.);
#705=ORIENTED_EDGE('',*,*,#704,.F.);
#706=DIRECTION('',(-0.573576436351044,0.819152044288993,0.));
#707=VECTOR('',#706,1.);
#708=CARTESIAN_POINT('',(3.32039488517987,-4.33132342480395,-15.));
#709=LINE('',#708,#707);
#710=EDGE_CURVE('E582',#658,#703,#709,.T.);
#711=ORIENTED_EDGE('',*,*,#710,.F.);
#712=EDGE_LOOP('',(#660,#661,#662,#663,#671,#679,#688,#696,#705,#711));
#713=FACE_BOUND('',#712,.T.);
#714=ADVANCED_FACE('F663',(#713),#652,.F.);
#715=CARTESIAN_POINT('',(0.862938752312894,-6.05205273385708,-15.));
#716=DIRECTION('',(0.,0.,-1.));
#717=DIRECTION('',(-0.573576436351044,0.819152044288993,0.));
#718=AXIS2_PLACEMENT_3D('',#715,#716,#717);
#719=PLANE('',#718);
#720=DIRECTION('',(-0.819152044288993,-0.573576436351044,0.));
#721=VECTOR('',#720,1.);
#722=CARTESIAN_POINT('',(-4.36016463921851,1.40731196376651,-15.));
#723=LINE('',#722,#721);
#724=EDGE_CURVE('E551',#658,#570,#723,.T.);
#725=ORIENTED_EDGE('',*,*,#724,.F.);
#726=ORIENTED_EDGE('',*,*,#710,.T.);
#727=DIRECTION('',(0.819152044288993,0.573576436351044,0.));
#728=VECTOR('',#727,1.);
#729=CARTESIAN_POINT('',(-10.608589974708,10.3309881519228,-15.));
#730=LINE('',#729,#728);
#731=EDGE_CURVE('E570',#578,#703,#730,.T.);
#732=ORIENTED_EDGE('',*,*,#731,.F.);
#733=ORIENTED_EDGE('',*,*,#579,.F.);
#734=EDGE_LOOP('',(#725,#726,#732,#733));
#735=FACE_BOUND('',#734,.T.);
#736=ADVANCED_FACE('F404',(#735),#719,.F.);
#737=CARTESIAN_POINT('',(6.59870311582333,-14.243573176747,15.));
#738=DIRECTION('',(0.,0.,1.));
#739=DIRECTION('',(0.573576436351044,-0.819152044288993,0.));
#740=AXIS2_PLACEMENT_3D('',#737,#738,#739);
#741=PLANE('',#740);
#742=DIRECTION('',(0.819152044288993,0.573576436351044,0.));
#743=VECTOR('',#742,1.);
#744=CARTESIAN_POINT('',(-4.36016463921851,1.40731196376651,15.));
#745=LINE('',#744,#743);
#746=EDGE_CURVE('E550',#612,#669,#745,.T.);
#747=ORIENTED_EDGE('',*,*,#746,.F.);
#748=ORIENTED_EDGE('',*,*,#613,.F.);
#749=DIRECTION('',(0.819152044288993,0.573576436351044,0.));
#750=VECTOR('',#749,1.);
#751=CARTESIAN_POINT('',(-10.608589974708,10.3309881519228,15.));
#752=LINE('',#751,#750);
#753=EDGE_CURVE('E595',#604,#677,#752,.T.);
#754=ORIENTED_EDGE('',*,*,#753,.T.);
#755=ORIENTED_EDGE('',*,*,#678,.T.);
#756=EDGE_LOOP('',(#747,#748,#754,#755));
#757=FACE_BOUND('',#756,.T.);
#758=ADVANCED_FACE('F573',(#757),#741,.F.);
#759=CARTESIAN_POINT('',(-10.608589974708,10.3309881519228,10.));
#760=DIRECTION('',(0.819152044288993,0.573576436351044,0.));
#761=DIRECTION('',(0.,0.,1.));
#762=AXIS2_PLACEMENT_3D('',#759,#760,#761);
#763=CYLINDRICAL_SURFACE('',#762,5.);
#764=ORIENTED_EDGE('',*,*,#687,.T.);
#765=ORIENTED_EDGE('',*,*,#753,.F.);
#766=ORIENTED_EDGE('',*,*,#605,.F.);
#767=DIRECTION('',(0.819152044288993,0.573576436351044,0.));
#768=VECTOR('',#767,1.);
#769=CARTESIAN_POINT('',(-13.4764721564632,14.4267483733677,10.));
#770=LINE('',#769,#768);
#771=EDGE_CURVE('E653',#595,#686,#770,.T.);
#772=ORIENTED_EDGE('',*,*,#771,.T.);
#773=EDGE_LOOP('',(#764,#765,#766,#772));
#774=FACE_BOUND('',#773,.T.);
#775=ADVANCED_FACE('F667',(#774),#763,.F.);
#776=CARTESIAN_POINT('',(-13.4764721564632,14.4267483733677,-10.));
#777=DIRECTION('',(-0.573576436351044,0.819152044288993,0.));
#778=DIRECTION('',(0.,0.,1.));
#779=AXIS2_PLACEMENT_3D('',#776,#777,#778);
#780=PLANE('',#779);
#781=ORIENTED_EDGE('',*,*,#695,.T.);
#782=ORIENTED_EDGE('',*,*,#771,.F.);
#783=ORIENTED_EDGE('',*,*,#596,.F.);
#784=DIRECTION('',(0.819152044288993,0.573576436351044,0.));
#785=VECTOR('',#784,1.);
#786=CARTESIAN_POINT('',(-13.4764721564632,14.4267483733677,-10.));
#787=LINE('',#786,#785);
#788=EDGE_CURVE('E654',#587,#694,#787,.T.);
#789=ORIENTED_EDGE('',*,*,#788,.T.);
#790=EDGE_LOOP('',(#781,#782,#783,#789));
#791=FACE_BOUND('',#790,.T.);
#792=ADVANCED_FACE('F665',(#791),#780,.F.);
#793=CARTESIAN_POINT('',(-10.608589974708,10.3309881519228,-10.));
#794=DIRECTION('',(0.819152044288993,0.573576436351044,0.));
#795=DIRECTION('',(0.,0.,1.));
#796=AXIS2_PLACEMENT_3D('',#793,#794,#795);
#797=CYLINDRICAL_SURFACE('',#796,5.);
#798=ORIENTED_EDGE('',*,*,#704,.T.);
#799=ORIENTED_EDGE('',*,*,#788,.F.);
#800=ORIENTED_EDGE('',*,*,#588,.F.);
#801=ORIENTED_EDGE('',*,*,#731,.T.);
#802=EDGE_LOOP('',(#798,#799,#800,#801));
#803=FACE_BOUND('',#802,.T.);
#804=ADVANCED_FACE('F659',(#803),#797,.F.);
#805=CARTESIAN_POINT('',(15.,-3.,-10.));
#806=DIRECTION('',(0.,1.,0.));
#807=DIRECTION('',(0.,0.,1.));
#808=AXIS2_PLACEMENT_3D('',#805,#806,#807);
#809=CYLINDRICAL_SURFACE('',#808,5.);
#810=CARTESIAN_POINT('',(15.,0.,-10.));
#811=DIRECTION('',(0.,1.,0.));
#812=DIRECTION('',(0.,0.,-1.));
#813=AXIS2_PLACEMENT_3D('',#810,#811,#812);
#814=CIRCLE('',#813,5.);
#815=CARTESIAN_POINT('',(20.,0.,-10.));
#816=VERTEX_POINT('',#815);
#817=CARTESIAN_POINT('',(15.,0.,-15.));
#818=VERTEX_POINT('',#817);
#819=EDGE_CURVE('E751',#816,#818,#814,.T.);
#820=ORIENTED_EDGE('',*,*,#819,.T.);
#821=DIRECTION('',(0.,1.,0.));
#822=VECTOR('',#821,1.);
#823=CARTESIAN_POINT('',(15.,-3.,-15.));
#824=LINE('',#823,#822);
#825=CARTESIAN_POINT('',(15.,-3.,-15.));
#826=VERTEX_POINT('',#825);
#827=EDGE_CURVE('E698',#826,#818,#824,.T.);
#828=ORIENTED_EDGE('',*,*,#827,.F.);
#829=CARTESIAN_POINT('',(15.,-3.,-10.));
#830=DIRECTION('',(0.,1.,0.));
#831=DIRECTION('',(0.,0.,-1.));
#832=AXIS2_PLACEMENT_3D('',#829,#830,#831);
#833=CIRCLE('',#832,5.);
#834=CARTESIAN_POINT('',(20.,-3.,-10.));
#835=VERTEX_POINT('',#834);
#836=EDGE_CURVE('E722',#835,#826,#833,.T.);
#837=ORIENTED_EDGE('',*,*,#836,.F.);
#838=DIRECTION('',(0.,1.,0.));
#839=VECTOR('',#838,1.);
#840=CARTESIAN_POINT('',(20.,-3.,-10.));
#841=LINE('',#840,#839);
#842=EDGE_CURVE('E749',#835,#816,#841,.T.);
#843=ORIENTED_EDGE('',*,*,#842,.T.);
#844=EDGE_LOOP('',(#820,#828,#837,#843));
#845=FACE_BOUND('',#844,.T.);
#846=ADVANCED_FACE('F787',(#845),#809,.F.);
#847=CARTESIAN_POINT('',(20.,-3.,-10.));
#848=DIRECTION('',(1.,0.,0.));
#849=DIRECTION('',(0.,0.,-1.));
#850=AXIS2_PLACEMENT_3D('',#847,#848,#849);
#851=PLANE('',#850);
#852=DIRECTION('',(0.,0.,-1.));
#853=VECTOR('',#852,1.);
#854=CARTESIAN_POINT('',(20.,0.,-10.));
#855=LINE('',#854,#853);
#856=CARTESIAN_POINT('',(20.,0.,10.));
#857=VERTEX_POINT('',#856);
#858=EDGE_CURVE('E746',#857,#816,#855,.T.);
#859=ORIENTED_EDGE('',*,*,#858,.T.);
#860=ORIENTED_EDGE('',*,*,#842,.F.);
#861=DIRECTION('',(0.,0.,-1.));
#862=VECTOR('',#861,1.);
#863=CARTESIAN_POINT('',(20.,-3.,-10.));
#864=LINE('',#863,#862);
#865=CARTESIAN_POINT('',(20.,-3.,10.));
#866=VERTEX_POINT('',#865);
#867=EDGE_CURVE('E725',#866,#835,#864,.T.);
#868=ORIENTED_EDGE('',*,*,#867,.F.);
#869=DIRECTION('',(0.,1.,0.));
#870=VECTOR('',#869,1.);
#871=CARTESIAN_POINT('',(20.,-3.,10.));
#872=LINE('',#871,#870);
#873=EDGE_CURVE('E744',#866,#857,#872,.T.);
#874=ORIENTED_EDGE('',*,*,#873,.T.);
#875=EDGE_LOOP('',(#859,#860,#868,#874));
#876=FACE_BOUND('',#875,.T.);
#877=ADVANCED_FACE('F782',(#876),#851,.F.);
#878=CARTESIAN_POINT('',(15.,-3.,10.));
#879=DIRECTION('',(0.,1.,0.));
#880=DIRECTION('',(0.,0.,1.));
#881=AXIS2_PLACEMENT_3D('',#878,#879,#880);
#882=CYLINDRICAL_SURFACE('',#881,5.);
#883=CARTESIAN_POINT('',(15.,0.,10.));
#884=DIRECTION('',(0.,1.,0.));
#885=DIRECTION('',(0.,0.,-1.));
#886=AXIS2_PLACEMENT_3D('',#883,#884,#885);
#887=CIRCLE('',#886,5.);
#888=CARTESIAN_POINT('',(15.,0.,15.));
#889=VERTEX_POINT('',#888);
#890=EDGE_CURVE('E741',#889,#857,#887,.T.);
#891=ORIENTED_EDGE('',*,*,#890,.T.);
#892=ORIENTED_EDGE('',*,*,#873,.F.);
#893=CARTESIAN_POINT('',(15.,-3.,10.));
#894=DIRECTION('',(0.,1.,0.));
#895=DIRECTION('',(0.,0.,-1.));
#896=AXIS2_PLACEMENT_3D('',#893,#894,#895);
#897=CIRCLE('',#896,5.);
#898=CARTESIAN_POINT('',(15.,-3.,15.));
#899=VERTEX_POINT('',#898);
#900=EDGE_CURVE('E728',#899,#866,#897,.T.);
#901=ORIENTED_EDGE('',*,*,#900,.F.);
#902=DIRECTION('',(0.,1.,0.));
#903=VECTOR('',#902,1.);
#904=CARTESIAN_POINT('',(15.,-3.,15.));
#905=LINE('',#904,#903);
#906=EDGE_CURVE('E738',#899,#889,#905,.T.);
#907=ORIENTED_EDGE('',*,*,#906,.T.);
#908=EDGE_LOOP('',(#891,#892,#901,#907));
#909=FACE_BOUND('',#908,.T.);
#910=ADVANCED_FACE('F780',(#909),#882,.F.);
#911=CARTESIAN_POINT('',(50.,-3.,50.));
#912=DIRECTION('',(1.,0.,0.));
#913=DIRECTION('',(0.,0.,-1.));
#914=AXIS2_PLACEMENT_3D('',#911,#912,#913);
#915=PLANE('',#914);
#916=DIRECTION('',(0.,0.,-1.));
#917=VECTOR('',#916,1.);
#918=CARTESIAN_POINT('',(50.,0.,50.));
#919=LINE('',#918,#917);
#920=CARTESIAN_POINT('',(50.,0.,50.));
#921=VERTEX_POINT('',#920);
#922=CARTESIAN_POINT('',(50.,0.,-50.));
#923=VERTEX_POINT('',#922);
#924=EDGE_CURVE('E705',#921,#923,#919,.T.);
#925=ORIENTED_EDGE('',*,*,#924,.F.);
#926=DIRECTION('',(0.,1.,0.));
#927=VECTOR('',#926,1.);
#928=CARTESIAN_POINT('',(50.,-3.,50.));
#929=LINE('',#928,#927);
#930=CARTESIAN_POINT('',(50.,-3.,50.));
#931=VERTEX_POINT('',#930);
#932=EDGE_CURVE('E647',#931,#921,#929,.T.);
#933=ORIENTED_EDGE('',*,*,#932,.F.);
#934=DIRECTION('',(0.,0.,-1.));
#935=VECTOR('',#934,1.);
#936=CARTESIAN_POINT('',(50.,-3.,50.));
#937=LINE('',#936,#935);
#938=CARTESIAN_POINT('',(50.,-3.,-50.));
#939=VERTEX_POINT('',#938);
#940=EDGE_CURVE('E735',#931,#939,#937,.T.);
#941=ORIENTED_EDGE('',*,*,#940,.T.);
#942=DIRECTION('',(0.,1.,0.));
#943=VECTOR('',#942,1.);
#944=CARTESIAN_POINT('',(50.,-3.,-50.));
#945=LINE('',#944,#943);
#946=EDGE_CURVE('E733',#939,#923,#945,.T.);
#947=ORIENTED_EDGE('',*,*,#946,.T.);
#948=EDGE_LOOP('',(#925,#933,#941,#947));
#949=FACE_BOUND('',#948,.T.);
#950=ADVANCED_FACE('F804',(#949),#915,.T.);
#951=CARTESIAN_POINT('',(50.,-3.,-50.));
#952=DIRECTION('',(0.,-1.,0.));
#953=DIRECTION('',(0.,0.,-1.));
#954=AXIS2_PLACEMENT_3D('',#951,#952,#953);
#955=PLANE('',#954);
#956=DIRECTION('',(0.,0.,1.));
#957=VECTOR('',#956,1.);
#958=CARTESIAN_POINT('',(4.10620287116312,-3.,-50.));
#959=LINE('',#958,#957);
#960=CARTESIAN_POINT('',(4.10620287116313,-3.,-50.));
#961=VERTEX_POINT('',#960);
#962=CARTESIAN_POINT('',(4.10620287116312,-3.,-15.));
#963=VERTEX_POINT('',#962);
#964=EDGE_CURVE('E757',#961,#963,#959,.T.);
#965=ORIENTED_EDGE('',*,*,#964,.F.);
#966=DIRECTION('',(-1.,0.,0.));
#967=VECTOR('',#966,1.);
#968=CARTESIAN_POINT('',(-50.,-3.,-50.));
#969=LINE('',#968,#967);
#970=EDGE_CURVE('E718',#939,#961,#969,.T.);
#971=ORIENTED_EDGE('',*,*,#970,.F.);
#972=ORIENTED_EDGE('',*,*,#940,.F.);
#973=DIRECTION('',(1.,0.,0.));
#974=VECTOR('',#973,1.);
#975=CARTESIAN_POINT('',(-50.,-3.,50.));
#976=LINE('',#975,#974);
#977=CARTESIAN_POINT('',(4.10620287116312,-3.,50.));
#978=VERTEX_POINT('',#977);
#979=EDGE_CURVE('E693',#978,#931,#976,.T.);
#980=ORIENTED_EDGE('',*,*,#979,.F.);
#981=DIRECTION('',(0.,0.,1.));
#982=VECTOR('',#981,1.);
#983=CARTESIAN_POINT('',(4.10620287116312,-3.,-50.));
#984=LINE('',#983,#982);
#985=CARTESIAN_POINT('',(4.10620287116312,-3.,15.));
#986=VERTEX_POINT('',#985);
#987=EDGE_CURVE('E639',#986,#978,#984,.T.);
#988=ORIENTED_EDGE('',*,*,#987,.F.);
#989=DIRECTION('',(1.,0.,0.));
#990=VECTOR('',#989,1.);
#991=CARTESIAN_POINT('',(-15.,-3.,15.));
#992=LINE('',#991,#990);
#993=EDGE_CURVE('E731',#986,#899,#992,.T.);
#994=ORIENTED_EDGE('',*,*,#993,.T.);
#995=ORIENTED_EDGE('',*,*,#900,.T.);
#996=ORIENTED_EDGE('',*,*,#867,.T.);
#997=ORIENTED_EDGE('',*,*,#836,.T.);
#998=DIRECTION('',(-1.,0.,0.));
#999=VECTOR('',#998,1.);
#1000=CARTESIAN_POINT('',(-4.99999999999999,-3.,-15.));
#1001=LINE('',#1000,#999);
#1002=EDGE_CURVE('E720',#826,#963,#1001,.T.);
#1003=ORIENTED_EDGE('',*,*,#1002,.T.);
#1004=EDGE_LOOP('',(#965,#971,#972,#980,#988,#994,#995,#996,#997,#1003));
#1005=FACE_BOUND('',#1004,.T.);
#1006=ADVANCED_FACE('F763',(#1005),#955,.T.);
#1007=CARTESIAN_POINT('',(-50.,-3.,-50.));
#1008=DIRECTION('',(0.,0.,-1.));
#1009=DIRECTION('',(-1.,0.,0.));
#1010=AXIS2_PLACEMENT_3D('',#1007,#1008,#1009);
#1011=PLANE('',#1010);
#1012=DIRECTION('',(0.,-1.,0.));
#1013=VECTOR('',#1012,1.);
#1014=CARTESIAN_POINT('',(4.10620287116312,-3.,-50.));
#1015=LINE('',#1014,#1013);
#1016=CARTESIAN_POINT('',(4.10620287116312,0.,-50.));
#1017=VERTEX_POINT('',#1016);
#1018=EDGE_CURVE('E754',#1017,#961,#1015,.T.);
#1019=ORIENTED_EDGE('',*,*,#1018,.F.);
#1020=DIRECTION('',(-1.,0.,0.));
#1021=VECTOR('',#1020,1.);
#1022=CARTESIAN_POINT('',(-50.,0.,-50.));
#1023=LINE('',#1022,#1021);
#1024=EDGE_CURVE('E716',#923,#1017,#1023,.T.);
#1025=ORIENTED_EDGE('',*,*,#1024,.F.);
#1026=ORIENTED_EDGE('',*,*,#946,.F.);
#1027=ORIENTED_EDGE('',*,*,#970,.T.);
#1028=EDGE_LOOP('',(#1019,#1025,#1026,#1027));
#1029=FACE_BOUND('',#1028,.T.);
#1030=ADVANCED_FACE('F799',(#1029),#1011,.T.);
#1031=CARTESIAN_POINT('',(50.,0.,-50.));
#1032=DIRECTION('',(0.,-1.,0.));
#1033=DIRECTION('',(0.,0.,-1.));
#1034=AXIS2_PLACEMENT_3D('',#1031,#1032,#1033);
#1035=PLANE('',#1034);
#1036=ORIENTED_EDGE('',*,*,#1024,.T.);
#1037=DIRECTION('',(0.,0.,1.));
#1038=VECTOR('',#1037,1.);
#1039=CARTESIAN_POINT('',(4.10620287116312,0.,-50.));
#1040=LINE('',#1039,#1038);
#1041=CARTESIAN_POINT('',(4.10620287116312,0.,-15.));
#1042=VERTEX_POINT('',#1041);
#1043=EDGE_CURVE('E713',#1017,#1042,#1040,.T.);
#1044=ORIENTED_EDGE('',*,*,#1043,.T.);
#1045=DIRECTION('',(-1.,0.,0.));
#1046=VECTOR('',#1045,1.);
#1047=CARTESIAN_POINT('',(5.00000000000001,0.,-15.));
#1048=LINE('',#1047,#1046);
#1049=EDGE_CURVE('E703',#818,#1042,#1048,.T.);
#1050=ORIENTED_EDGE('',*,*,#1049,.F.);
#1051=ORIENTED_EDGE('',*,*,#819,.F.);
#1052=ORIENTED_EDGE('',*,*,#858,.F.);
#1053=ORIENTED_EDGE('',*,*,#890,.F.);
#1054=DIRECTION('',(1.,0.,0.));
#1055=VECTOR('',#1054,1.);
#1056=CARTESIAN_POINT('',(15.,0.,15.));
#1057=LINE('',#1056,#1055);
#1058=CARTESIAN_POINT('',(4.10620287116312,0.,15.));
#1059=VERTEX_POINT('',#1058);
#1060=EDGE_CURVE('E695',#1059,#889,#1057,.T.);
#1061=ORIENTED_EDGE('',*,*,#1060,.F.);
#1062=DIRECTION('',(0.,0.,1.));
#1063=VECTOR('',#1062,1.);
#1064=CARTESIAN_POINT('',(4.10620287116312,0.,-50.));
#1065=LINE('',#1064,#1063);
#1066=CARTESIAN_POINT('',(4.10620287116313,0.,50.));
#1067=VERTEX_POINT('',#1066);
#1068=EDGE_CURVE('E710',#1059,#1067,#1065,.T.);
#1069=ORIENTED_EDGE('',*,*,#1068,.T.);
#1070=DIRECTION('',(1.,0.,0.));
#1071=VECTOR('',#1070,1.);
#1072=CARTESIAN_POINT('',(-50.,0.,50.));
#1073=LINE('',#1072,#1071);
#1074=EDGE_CURVE('E708',#1067,#921,#1073,.T.);
#1075=ORIENTED_EDGE('',*,*,#1074,.T.);
#1076=ORIENTED_EDGE('',*,*,#924,.T.);
#1077=EDGE_LOOP('',(#1036,#1044,#1050,#1051,#1052,#1053,#1061,#1069,#1075,#1076));
#1078=FACE_BOUND('',#1077,.T.);
#1079=ADVANCED_FACE('F771',(#1078),#1035,.F.);
#1080=CARTESIAN_POINT('',(5.00000000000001,-3.,-15.));
#1081=DIRECTION('',(0.,0.,-1.));
#1082=DIRECTION('',(-1.,0.,0.));
#1083=AXIS2_PLACEMENT_3D('',#1080,#1081,#1082);
#1084=PLANE('',#1083);
#1085=ORIENTED_EDGE('',*,*,#1049,.T.);
#1086=DIRECTION('',(0.,-1.,0.));
#1087=VECTOR('',#1086,1.);
#1088=CARTESIAN_POINT('',(4.10620287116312,-3.,-15.));
#1089=LINE('',#1088,#1087);
#1090=EDGE_CURVE('E700',#1042,#963,#1089,.T.);
#1091=ORIENTED_EDGE('',*,*,#1090,.T.);
#1092=ORIENTED_EDGE('',*,*,#1002,.F.);
#1093=ORIENTED_EDGE('',*,*,#827,.T.);
#1094=EDGE_LOOP('',(#1085,#1091,#1092,#1093));
#1095=FACE_BOUND('',#1094,.T.);
#1096=ADVANCED_FACE('F789',(#1095),#1084,.F.);
#1097=CARTESIAN_POINT('',(15.,-3.,15.));
#1098=DIRECTION('',(0.,0.,1.));
#1099=DIRECTION('',(1.,0.,0.));
#1100=AXIS2_PLACEMENT_3D('',#1097,#1098,#1099);
#1101=PLANE('',#1100);
#1102=ORIENTED_EDGE('',*,*,#993,.F.);
#1103=DIRECTION('',(0.,1.,0.));
#1104=VECTOR('',#1103,1.);
#1105=CARTESIAN_POINT('',(4.10620287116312,-3.,15.));
#1106=LINE('',#1105,#1104);
#1107=EDGE_CURVE('E558',#986,#1059,#1106,.T.);
#1108=ORIENTED_EDGE('',*,*,#1107,.T.);
#1109=ORIENTED_EDGE('',*,*,#1060,.T.);
#1110=ORIENTED_EDGE('',*,*,#906,.F.);
#1111=EDGE_LOOP('',(#1102,#1108,#1109,#1110));
#1112=FACE_BOUND('',#1111,.T.);
#1113=ADVANCED_FACE('F776',(#1112),#1101,.F.);
#1114=CARTESIAN_POINT('',(-50.,-3.,50.));
#1115=DIRECTION('',(0.,0.,1.));
#1116=DIRECTION('',(1.,0.,0.));
#1117=AXIS2_PLACEMENT_3D('',#1114,#1115,#1116);
#1118=PLANE('',#1117);
#1119=DIRECTION('',(0.,1.,0.));
#1120=VECTOR('',#1119,1.);
#1121=CARTESIAN_POINT('',(4.10620287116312,-3.,50.));
#1122=LINE('',#1121,#1120);
#1123=EDGE_CURVE('E679',#978,#1067,#1122,.T.);
#1124=ORIENTED_EDGE('',*,*,#1123,.F.);
#1125=ORIENTED_EDGE('',*,*,#979,.T.);
#1126=ORIENTED_EDGE('',*,*,#932,.T.);
#1127=ORIENTED_EDGE('',*,*,#1074,.F.);
#1128=EDGE_LOOP('',(#1124,#1125,#1126,#1127));
#1129=FACE_BOUND('',#1128,.T.);
#1130=ADVANCED_FACE('F767',(#1129),#1118,.T.);
#1131=CARTESIAN_POINT('',(4.10620287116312,7.33552631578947,-50.));
#1132=DIRECTION('',(0.,0.,-1.));
#1133=DIRECTION('',(-1.,0.,0.));
#1134=AXIS2_PLACEMENT_3D('',#1131,#1132,#1133);
#1135=PLANE('',#1134);
#1136=ORIENTED_EDGE('',*,*,#540,.F.);
#1137=CARTESIAN_POINT('',(4.10620287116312,7.33552631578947,-50.));
#1138=DIRECTION('',(0.,0.,-1.));
#1139=DIRECTION('',(-1.,0.,0.));
#1140=AXIS2_PLACEMENT_3D('',#1137,#1138,#1139);
#1141=CIRCLE('',#1140,7.33552631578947);
#1142=EDGE_CURVE('E687',#529,#1017,#1141,.F.);
#1143=ORIENTED_EDGE('',*,*,#1142,.T.);
#1144=ORIENTED_EDGE('',*,*,#1018,.T.);
#1145=CARTESIAN_POINT('',(4.10620287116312,7.33552631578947,-50.));
#1146=DIRECTION('',(0.,0.,1.));
#1147=DIRECTION('',(-1.,0.,0.));
#1148=AXIS2_PLACEMENT_3D('',#1145,#1146,#1147);
#1149=CIRCLE('',#1148,10.3355263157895);
#1150=EDGE_CURVE('E684',#539,#961,#1149,.T.);
#1151=ORIENTED_EDGE('',*,*,#1150,.F.);
#1152=EDGE_LOOP('',(#1136,#1143,#1144,#1151));
#1153=FACE_BOUND('',#1152,.T.);
#1154=ADVANCED_FACE('F793',(#1153),#1135,.T.);
#1155=CARTESIAN_POINT('',(4.10620287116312,7.33552631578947,-15.));
#1156=DIRECTION('',(0.,0.,1.));
#1157=DIRECTION('',(1.,0.,0.));
#1158=AXIS2_PLACEMENT_3D('',#1155,#1156,#1157);
#1159=PLANE('',#1158);
#1160=CARTESIAN_POINT('',(4.10620287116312,7.33552631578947,-15.));
#1161=DIRECTION('',(0.,0.,-1.));
#1162=DIRECTION('',(-1.,0.,0.));
#1163=AXIS2_PLACEMENT_3D('',#1160,#1161,#1162);
#1164=CIRCLE('',#1163,7.33552631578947);
#1165=EDGE_CURVE('E624',#1042,#658,#1164,.T.);
#1166=ORIENTED_EDGE('',*,*,#1165,.T.);
#1167=ORIENTED_EDGE('',*,*,#724,.T.);
#1168=CARTESIAN_POINT('',(4.10620287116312,7.33552631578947,-15.));
#1169=DIRECTION('',(0.,0.,-1.));
#1170=DIRECTION('',(-1.,0.,0.));
#1171=AXIS2_PLACEMENT_3D('',#1168,#1169,#1170);
#1172=CIRCLE('',#1171,10.3355263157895);
#1173=EDGE_CURVE('E427',#963,#570,#1172,.T.);
#1174=ORIENTED_EDGE('',*,*,#1173,.F.);
#1175=ORIENTED_EDGE('',*,*,#1090,.F.);
#1176=EDGE_LOOP('',(#1166,#1167,#1174,#1175));
#1177=FACE_BOUND('',#1176,.T.);
#1178=ADVANCED_FACE('F621',(#1177),#1159,.T.);
#1179=CARTESIAN_POINT('',(4.10620287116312,7.33552631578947,3.57552644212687));
#1180=DIRECTION('',(0.,0.,-1.));
#1181=DIRECTION('',(-1.,0.,0.));
#1182=AXIS2_PLACEMENT_3D('',#1179,#1180,#1181);
#1183=CYLINDRICAL_SURFACE('',#1182,10.3355263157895);
#1184=ORIENTED_EDGE('',*,*,#964,.T.);
#1185=ORIENTED_EDGE('',*,*,#1173,.T.);
#1186=ORIENTED_EDGE('',*,*,#571,.F.);
#1187=ORIENTED_EDGE('',*,*,#1150,.T.);
#1188=EDGE_LOOP('',(#1184,#1185,#1186,#1187));
#1189=FACE_BOUND('',#1188,.T.);
#1190=ADVANCED_FACE('F791',(#1189),#1183,.T.);
#1191=CARTESIAN_POINT('',(4.10620287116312,7.33552631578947,3.57552644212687));
#1192=DIRECTION('',(0.,0.,-1.));
#1193=DIRECTION('',(-1.,0.,0.));
#1194=AXIS2_PLACEMENT_3D('',#1191,#1192,#1193);
#1195=CYLINDRICAL_SURFACE('',#1194,7.33552631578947);
#1196=ORIENTED_EDGE('',*,*,#1043,.F.);
#1197=ORIENTED_EDGE('',*,*,#1142,.F.);
#1198=ORIENTED_EDGE('',*,*,#659,.T.);
#1199=ORIENTED_EDGE('',*,*,#1165,.F.);
#1200=EDGE_LOOP('',(#1196,#1197,#1198,#1199));
#1201=FACE_BOUND('',#1200,.T.);
#1202=ADVANCED_FACE('F801',(#1201),#1195,.F.);
#1203=CARTESIAN_POINT('',(4.10620287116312,7.33552631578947,15.));
#1204=DIRECTION('',(0.,0.,-1.));
#1205=DIRECTION('',(-1.,0.,0.));
#1206=AXIS2_PLACEMENT_3D('',#1203,#1204,#1205);
#1207=PLANE('',#1206);
#1208=ORIENTED_EDGE('',*,*,#746,.T.);
#1209=CARTESIAN_POINT('',(4.10620287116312,7.33552631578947,15.));
#1210=DIRECTION('',(0.,0.,-1.));
#1211=DIRECTION('',(-1.,0.,0.));
#1212=AXIS2_PLACEMENT_3D('',#1209,#1210,#1211);
#1213=CIRCLE('',#1212,7.33552631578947);
#1214=EDGE_CURVE('E675',#669,#1059,#1213,.F.);
#1215=ORIENTED_EDGE('',*,*,#1214,.T.);
#1216=ORIENTED_EDGE('',*,*,#1107,.F.);
#1217=CARTESIAN_POINT('',(4.10620287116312,7.33552631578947,15.));
#1218=DIRECTION('',(0.,0.,1.));
#1219=DIRECTION('',(1.,0.,0.));
#1220=AXIS2_PLACEMENT_3D('',#1217,#1218,#1219);
#1221=CIRCLE('',#1220,10.3355263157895);
#1222=EDGE_CURVE('E544',#612,#986,#1221,.T.);
#1223=ORIENTED_EDGE('',*,*,#1222,.F.);
#1224=EDGE_LOOP('',(#1208,#1215,#1216,#1223));
#1225=FACE_BOUND('',#1224,.T.);
#1226=ADVANCED_FACE('F554',(#1225),#1207,.T.);
#1227=CARTESIAN_POINT('',(4.10620287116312,7.33552631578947,50.));
#1228=DIRECTION('',(0.,0.,1.));
#1229=DIRECTION('',(1.,0.,0.));
#1230=AXIS2_PLACEMENT_3D('',#1227,#1228,#1229);
#1231=PLANE('',#1230);
#1232=CARTESIAN_POINT('',(4.10620287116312,7.33552631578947,50.));
#1233=DIRECTION('',(0.,0.,-1.));
#1234=DIRECTION('',(-1.,0.,0.));
#1235=AXIS2_PLACEMENT_3D('',#1232,#1233,#1234);
#1236=CIRCLE('',#1235,7.33552631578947);
#1237=EDGE_CURVE('E559',#1067,#499,#1236,.T.);
#1238=ORIENTED_EDGE('',*,*,#1237,.T.);
#1239=ORIENTED_EDGE('',*,*,#500,.F.);
#1240=CARTESIAN_POINT('',(4.10620287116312,7.33552631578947,50.));
#1241=DIRECTION('',(0.,0.,-1.));
#1242=DIRECTION('',(1.,0.,0.));
#1243=AXIS2_PLACEMENT_3D('',#1240,#1241,#1242);
#1244=CIRCLE('',#1243,10.3355263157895);
#1245=EDGE_CURVE('E419',#978,#491,#1244,.T.);
#1246=ORIENTED_EDGE('',*,*,#1245,.F.);
#1247=ORIENTED_EDGE('',*,*,#1123,.T.);
#1248=EDGE_LOOP('',(#1238,#1239,#1246,#1247));
#1249=FACE_BOUND('',#1248,.T.);
#1250=ADVANCED_FACE('F677',(#1249),#1231,.T.);
#1251=CARTESIAN_POINT('',(4.10620287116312,7.33552631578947,68.5755264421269));
#1252=DIRECTION('',(0.,0.,-1.));
#1253=DIRECTION('',(-1.,0.,0.));
#1254=AXIS2_PLACEMENT_3D('',#1251,#1252,#1253);
#1255=CYLINDRICAL_SURFACE('',#1254,10.3355263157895);
#1256=ORIENTED_EDGE('',*,*,#987,.T.);
#1257=ORIENTED_EDGE('',*,*,#1245,.T.);
#1258=ORIENTED_EDGE('',*,*,#619,.F.);
#1259=ORIENTED_EDGE('',*,*,#1222,.T.);
#1260=EDGE_LOOP('',(#1256,#1257,#1258,#1259));
#1261=FACE_BOUND('',#1260,.T.);
#1262=ADVANCED_FACE('F543',(#1261),#1255,.T.);
#1263=CARTESIAN_POINT('',(4.10620287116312,7.33552631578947,68.5755264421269));
#1264=DIRECTION('',(0.,0.,-1.));
#1265=DIRECTION('',(-1.,0.,0.));
#1266=AXIS2_PLACEMENT_3D('',#1263,#1264,#1265);
#1267=CYLINDRICAL_SURFACE('',#1266,7.33552631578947);
#1268=ORIENTED_EDGE('',*,*,#1068,.F.);
#1269=ORIENTED_EDGE('',*,*,#1214,.F.);
#1270=ORIENTED_EDGE('',*,*,#670,.T.);
#1271=ORIENTED_EDGE('',*,*,#1237,.F.);
#1272=EDGE_LOOP('',(#1268,#1269,#1270,#1271));
#1273=FACE_BOUND('',#1272,.T.);
#1274=ADVANCED_FACE('F673',(#1273),#1267,.F.);
#1275=CLOSED_SHELL('',(#518,#558,#630,#647,#714,#736,#758,#775,#792,#804,#846,#877,#910,#950,
#1006,#1030,#1079,#1096,#1113,#1130,#1154,#1178,#1190,#1202,#1226,#1250,#1262,#1274));
#1276=MANIFOLD_SOLID_BREP('B7',#1275);
#1277=ADVANCED_BREP_SHAPE_REPRESENTATION('',(#18,#478,#1276),#14);
#1278=SHAPE_DEFINITION_REPRESENTATION(#9,#1277);
ENDSEC;
END-ISO-10303-21;
